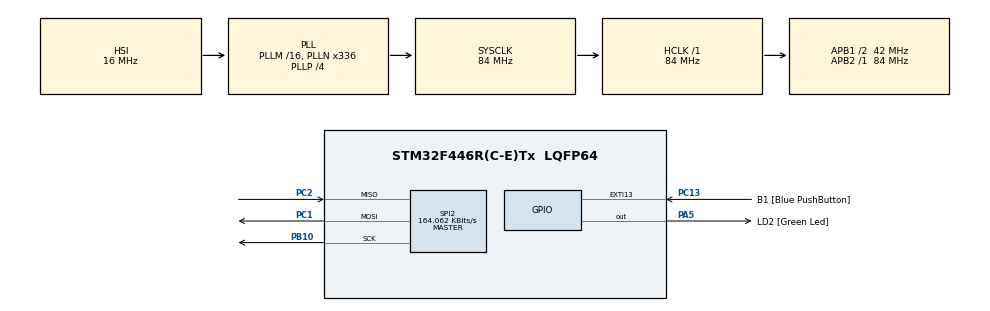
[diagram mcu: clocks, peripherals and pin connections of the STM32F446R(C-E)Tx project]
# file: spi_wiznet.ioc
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Dma.Request0=SPI2_RX
Dma.SPI2_RX.0.Direction=DMA_PERIPH_TO_MEMORY
Dma.SPI2_RX.0.FIFOMode=DMA_FIFOMODE_ENABLE
Dma.SPI2_RX.0.FIFOThreshold=DMA_FIFO_THRESHOLD_FULL
Dma.SPI2_RX.0.Instance=DMA1_Stream3
Dma.SPI2_RX.0.MemBurst=DMA_MBURST_SINGLE
Dma.SPI2_RX.0.MemDataAlignment=DMA_MDATAALIGN_BYTE
Dma.SPI2_RX.0.MemInc=DMA_MINC_ENABLE
Dma.SPI2_RX.0.Mode=DMA_NORMAL
Dma.SPI2_RX.0.PeriphBurst=DMA_PBURST_SINGLE
Dma.SPI2_RX.0.PeriphDataAlignment=DMA_PDATAALIGN_BYTE
Dma.SPI2_RX.0.PeriphInc=DMA_PINC_DISABLE
Dma.SPI2_RX.0.Priority=DMA_PRIORITY_LOW
Mcu.Family=STM32F4
Mcu.Name=STM32F446R(C-E)Tx
Mcu.Package=LQFP64
NVIC.DMA1_Stream3_IRQn=true\:0\:0\:false\:false\:true\:false\:true
NVIC.EXTI15_10_IRQn=true\:0\:0\:false\:false\:true\:true\:true
NVIC.PriorityGroup=NVIC_PRIORITYGROUP_0
NVIC.SPI2_IRQn=true\:0\:0\:false\:false\:true\:true\:true
NVIC.TIM3_IRQn=true\:0\:0\:false\:false\:true\:true\:true
PA13.GPIO_Label=TMS
PA13.Signal=SYS_JTMS-SWDIO
PA14.GPIO_Label=TCK
PA14.Signal=SYS_JTCK-SWCLK
PA2.GPIO_Label=USART_TX
PA2.Signal=USART2_TX
PA3.GPIO_Label=USART_RX
PA3.Signal=USART2_RX
PA5.GPIO_Label=LD2 [Green Led]
PA5.Signal=GPIO_Output
PB10.Mode=Full_Duplex_Master
PB10.Signal=SPI2_SCK
PB3.GPIO_Label=SWO
PB3.Signal=SYS_JTDO-SWO
PC1.Mode=Full_Duplex_Master
PC1.Signal=SPI2_MOSI
PC13.GPIO_Label=B1 [Blue PushButton]
PC13.GPIO_ModeDefaultEXTI=GPIO_MODE_IT_FALLING
PC13.Signal=GPXTI13
PC14-OSC32_IN.Signal=RCC_OSC32_IN
PC15-OSC32_OUT.Signal=RCC_OSC32_OUT
PC2.Mode=Full_Duplex_Master
PC2.Signal=SPI2_MISO
PH0-OSC_IN.Signal=RCC_OSC_IN
PH1-OSC_OUT.Signal=RCC_OSC_OUT
ProjectManager.HeapSize=0x200
ProjectManager.StackSize=0x400
ProjectManager.TargetToolchain=MDK-ARM V5
RCC.AHBFreq_Value=84000000
RCC.APB1CLKDivider=RCC_HCLK_DIV2
RCC.APB1Freq_Value=42000000
RCC.APB1TimFreq_Value=84000000
RCC.APB2Freq_Value=84000000
RCC.APB2TimFreq_Value=84000000
RCC.CortexFreq_Value=84000000
RCC.FLatency-AdvancedSettings=FLASH_LATENCY_2
RCC.HCLKFreq_Value=84000000
RCC.HSE_VALUE=8000000
RCC.HSI_VALUE=16000000
RCC.LSE_VALUE=32768
RCC.PLLN=336
RCC.PLLP=RCC_PLLP_DIV4
RCC.SYSCLKFreq_VALUE=84000000
RCC.SYSCLKSource=RCC_SYSCLKSOURCE_PLLCLK
RCC.USBFreq_Value=168000000
RCC.VCOOutputFreq_Value=336000000
SPI2.BaudRatePrescaler=SPI_BAUDRATEPRESCALER_256
SPI2.CLKPhase=SPI_PHASE_1EDGE
SPI2.CLKPolarity=SPI_POLARITY_LOW
SPI2.CalculateBaudRate=164.062 KBits/s
SPI2.Direction=SPI_DIRECTION_2LINES
SPI2.Mode=SPI_MODE_MASTER
SPI2.VirtualType=VM_MASTER
TIM3.Channel-Output\ Compare1\ No\ Output=TIM_CHANNEL_1
TIM3.Period=1000
TIM3.Prescaler=84
VP_TIM3_VS_OPM.Mode=OPM_bit
VP_TIM3_VS_no_output1.Mode=Output Compare1 No Output
board=NUCLEO-F446RE

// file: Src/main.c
/**
  ******************************************************************************
  * File Name          : main.c
  * Description        : Main program body
  ******************************************************************************
  ** This notice applies to any and all portions of this file
  * that are not between comment pairs USER CODE BEGIN and
  * USER CODE END. Other portions of this file, whether
  * inserted by the user or by software development tools
  * are owned by their respective copyright owners.
  *
  * COPYRIGHT(c) 2020 STMicroelectronics
  *
  * Redistribution and use in source and binary forms, with or without modification,
  * are permitted provided that the following conditions are met:
  *   1. Redistributions of source code must retain the above copyright notice,
  *      this list of conditions and the following disclaimer.
  *   2. Redistributions in binary form must reproduce the above copyright notice,
  *      this list of conditions and the following disclaimer in the documentation
  *      and/or other materials provided with the distribution.
  *   3. Neither the name of STMicroelectronics nor the names of its contributors
  *      may be used to endorse or promote products derived from this software
  *      without specific prior written permission.
  *
  * THIS SOFTWARE IS PROVIDED BY THE COPYRIGHT HOLDERS AND CONTRIBUTORS "AS IS"
  * AND ANY EXPRESS OR IMPLIED WARRANTIES, INCLUDING, BUT NOT LIMITED TO, THE
  * IMPLIED WARRANTIES OF MERCHANTABILITY AND FITNESS FOR A PARTICULAR PURPOSE ARE
  * DISCLAIMED. IN NO EVENT SHALL THE COPYRIGHT HOLDER OR CONTRIBUTORS BE LIABLE
  * FOR ANY DIRECT, INDIRECT, INCIDENTAL, SPECIAL, EXEMPLARY, OR CONSEQUENTIAL
  * DAMAGES (INCLUDING, BUT NOT LIMITED TO, PROCUREMENT OF SUBSTITUTE GOODS OR
  * SERVICES; LOSS OF USE, DATA, OR PROFITS; OR BUSINESS INTERRUPTION) HOWEVER
  * CAUSED AND ON ANY THEORY OF LIABILITY, WHETHER IN CONTRACT, STRICT LIABILITY,
  * OR TORT (INCLUDING NEGLIGENCE OR OTHERWISE) ARISING IN ANY WAY OUT OF THE USE
  * OF THIS SOFTWARE, EVEN IF ADVISED OF THE POSSIBILITY OF SUCH DAMAGE.
  *
  ******************************************************************************
  */

#include "main.h"
#include "stm32f4xx_hal.h"

/* USER CODE BEGIN Includes */
#include "stdbool.h"
#include "w5500.h"
#include "socket.h"
/* USER CODE END Includes */

SPI_HandleTypeDef hspi2;
DMA_HandleTypeDef hdma_spi2_rx;

TIM_HandleTypeDef htim3;

/* USER CODE BEGIN PV */
/* Private variables ---------------------------------------------------------*/
bool send_spi_flag = false;
wiz_NetInfo gWIZNETINFO = {
.mac = {0x00,0x08,0xff,0xad,0x56,0x16},
	.ip = {192,168,0,8},
		.sn = {255,255,255,0},
			.gw = {192,168,0,1},
				.dns = {0,0,0,0},
					.dhcp = NETINFO_STATIC};
/* USER CODE END PV */

void SystemClock_Config(void);
static void MX_GPIO_Init(void);
static void MX_DMA_Init(void);
static void MX_SPI2_Init(void);
static void MX_TIM3_Init(void);

/* USER CODE BEGIN PFP */
/* Private function prototypes -----------------------------------------------*/
void W5500_Select(void);
void W5500_Unselect(void);
void W5500_ReadBuff(uint8_t* buff,uint16_t len);
void W5500_WriteBuff(uint8_t* buff,uint16_t len);
uint8_t W5500_ReadByte(void);
void W5500_WriteByte(uint8_t byte);
/* USER CODE END PFP */

/* USER CODE BEGIN 0 */
//extern HAL_StatusTypeDef InitW5500(InitStructW5500_t Settings);
void InitStructSettings(void);
InitStructW5500_t Settings;
HAL_StatusTypeDef state_send_spi;
uint8_t data_from_spi[4] = {0x00,0x01,0x01,0x00};
uint8_t dest_ip[4] = {192,168,0,1};
uint16_t dest_port = 5777;
uint8_t dest_data[10] = {'1','2','3','4','5','6','7','8','9','0'};
uint8_t https_ok[] =  {"HTTP/1.1 200 OK\r\nContent-Type: text/html\r\nContent-Length:\r\n"};
uint8_t https_data[] = {"<html>\r\n<head>\r\n<meta http-equiv='Content-Type' content='text/html;charset=utf-8'>\r\n<title>МУК на связи)</title>\r\n</head>\r\n<body>\r\n<h1>НИИ Нептун</h1>\r\n<p>Установка сеанса связи удалась</p>\r\n</body>\r\n</html>\r\n\r\n"};//{"<html><head><title>HELLO WORLD!</title></head>"};
uint8_t send_ok[] = {"200 OK"};
uint8_t rx_tx_buffer_size[] = {2,2,2,2,2,2,2,2};
int32_t state_w = 0;
uint32_t leng_data = 0;
uint8_t  addr_gets[4] = {0};
uint16_t port_gets = 0;
uint8_t  data_gets[1024] = {0};
int  len_gets = 0;
/* USER CODE END 0 */

int main(void)
{

  /* MCU Configuration----------------------------------------------------------*/

  /* Reset of all peripherals, Initializes the Flash interface and the Systick. */
  HAL_Init();

  /* Configure the system clock */
  SystemClock_Config();

  /* Initialize all configured peripherals */
  MX_GPIO_Init();
  MX_DMA_Init();
  MX_SPI2_Init();
  MX_TIM3_Init();

  /* USER CODE BEGIN 2 */
	HAL_GPIO_WritePin(W5500_RESET_GPIO_Port,W5500_RESET_Pin,GPIO_PIN_SET);
	//InitStructSettings();
	for(int i = 0; i < 15000;i++)
	{
		__nop();
	}
	//HAL_GPIO_TogglePin(W5500_RESET_GPIO_Port,W5500_RESET_Pin);
	for(uint32_t i = 0; i < 1000000;i++)
	{
		__nop();
	}

	reg_wizchip_cs_cbfunc(W5500_Select,W5500_Unselect);
	reg_wizchip_spi_cbfunc(W5500_ReadByte,W5500_WriteByte);
	reg_wizchip_spiburst_cbfunc(W5500_ReadBuff,W5500_WriteBuff);

	wizchip_init(rx_tx_buffer_size,rx_tx_buffer_size);
	wizchip_setnetinfo(&gWIZNETINFO);
	ctlnetwork(CN_SET_NETINFO,(void*)&gWIZNETINFO);
	/*настроим нулевой сокет как TCP*/
	socket(0,Sn_MR_TCP,80,0);
	/*запустим сервер на нулевом сокете*/
	listen(0);
	/*настроим первый сокет как UDP*/
	socket(1,Sn_MR_UDP,7747,0);

	HAL_TIM_OC_Start_IT(&htim3,TIM_CHANNEL_1);

	/* USER CODE END 2 */

  /* Infinite loop */
  /* USER CODE BEGIN WHILE */
  while (1)
  {
			/*запустим сервер на нулевом сокете*/
//	listen(0);
//		if(send_spi_flag)
//		{
//      //state_w = send(0,dest_data,sizeof(dest_data));
//			state_w = sendto(1,dest_data,sizeof(dest_data),dest_ip,56589);
//			send_spi_flag = false;
//		}
//		len_gets = getSn_RX_RSR(1);
//		if(len_gets != 0)
//		{
//			leng_data =  recvfrom(1,data_gets,len_gets,addr_gets,&port_gets);
//		}
//		len_gets = getSn_RX_RSR(0);
//		if(len_gets != 0)
//		{
//			//leng_data =  recvfrom(0,data_gets,len_gets,addr_gets,&port_gets);
//			getsockopt(0,SO_DESTIP,addr_gets);
//			send(0,https_data,sizeof(https_data));
//			disconnect(0);
//			close(0);
//		}
		socket(0,Sn_MR_TCP,80,0);
		/*запустим сервер на нулевом сокете*/
		listen(0);

		while(getSn_SR(0) == SOCK_LISTEN)
		{
			HAL_Delay(2);
		}

		HAL_Delay(500);

		getsockopt(0,SO_DESTIP,addr_gets);

		len_gets = getSn_RX_RSR(0);

		if(len_gets != 0)
		{
			//leng_data =  recvfrom(0,data_gets,len_gets,addr_gets,&port_gets);

			leng_data =   recv(0, data_gets,len_gets);
	  }
		send(0,https_ok,sizeof(https_ok));
		HAL_Delay(100);
		send(0,https_data,sizeof(https_data));
		HAL_Delay(500);
		disconnect(0);
		HAL_Delay(500);
		close(0);

		HAL_Delay(500);

/* USER CODE END WHILE */

  }

}

/** System Clock Configuration
*/
void SystemClock_Config(void)
{

  RCC_OscInitTypeDef RCC_OscInitStruct;
  RCC_ClkInitTypeDef RCC_ClkInitStruct;

    /**Configure the main internal regulator output voltage
    */
  __HAL_RCC_PWR_CLK_ENABLE();

  __HAL_PWR_VOLTAGESCALING_CONFIG(PWR_REGULATOR_VOLTAGE_SCALE3);

    /**Initializes the CPU, AHB and APB busses clocks
    */
  RCC_OscInitStruct.OscillatorType = RCC_OSCILLATORTYPE_HSI;
  RCC_OscInitStruct.HSIState = RCC_HSI_ON;
  RCC_OscInitStruct.HSICalibrationValue = 16;
  RCC_OscInitStruct.PLL.PLLState = RCC_PLL_ON;
  RCC_OscInitStruct.PLL.PLLSource = RCC_PLLSOURCE_HSI;
  RCC_OscInitStruct.PLL.PLLM = 16;
  RCC_OscInitStruct.PLL.PLLN = 336;
  RCC_OscInitStruct.PLL.PLLP = RCC_PLLP_DIV4;
  RCC_OscInitStruct.PLL.PLLQ = 2;
  RCC_OscInitStruct.PLL.PLLR = 2;
  if (HAL_RCC_OscConfig(&RCC_OscInitStruct) != HAL_OK)
  {
    _Error_Handler(__FILE__, __LINE__);
  }

    /**Initializes the CPU, AHB and APB busses clocks
    */
  RCC_ClkInitStruct.ClockType = RCC_CLOCKTYPE_HCLK|RCC_CLOCKTYPE_SYSCLK
                              |RCC_CLOCKTYPE_PCLK1|RCC_CLOCKTYPE_PCLK2;
  RCC_ClkInitStruct.SYSCLKSource = RCC_SYSCLKSOURCE_PLLCLK;
  RCC_ClkInitStruct.AHBCLKDivider = RCC_SYSCLK_DIV1;
  RCC_ClkInitStruct.APB1CLKDivider = RCC_HCLK_DIV2;
  RCC_ClkInitStruct.APB2CLKDivider = RCC_HCLK_DIV1;

  if (HAL_RCC_ClockConfig(&RCC_ClkInitStruct, FLASH_LATENCY_2) != HAL_OK)
  {
    _Error_Handler(__FILE__, __LINE__);
  }

    /**Configure the Systick interrupt time
    */
  HAL_SYSTICK_Config(HAL_RCC_GetHCLKFreq()/1000);

    /**Configure the Systick
    */
  HAL_SYSTICK_CLKSourceConfig(SYSTICK_CLKSOURCE_HCLK);

  /* SysTick_IRQn interrupt configuration */
  HAL_NVIC_SetPriority(SysTick_IRQn, 0, 0);
}

/* SPI2 init function */
static void MX_SPI2_Init(void)
{

  /* SPI2 parameter configuration*/
  hspi2.Instance = SPI2;
  hspi2.Init.Mode = SPI_MODE_MASTER;
  hspi2.Init.Direction = SPI_DIRECTION_2LINES;
  hspi2.Init.DataSize = SPI_DATASIZE_8BIT;
  hspi2.Init.CLKPolarity = SPI_POLARITY_LOW;
  hspi2.Init.CLKPhase = SPI_PHASE_1EDGE;
  hspi2.Init.NSS = SPI_NSS_SOFT;
  hspi2.Init.BaudRatePrescaler = SPI_BAUDRATEPRESCALER_64;
  hspi2.Init.FirstBit = SPI_FIRSTBIT_MSB;
  hspi2.Init.TIMode = SPI_TIMODE_DISABLE;
  hspi2.Init.CRCCalculation = SPI_CRCCALCULATION_DISABLE;
  hspi2.Init.CRCPolynomial = 10;
  if (HAL_SPI_Init(&hspi2) != HAL_OK)
  {
    _Error_Handler(__FILE__, __LINE__);
  }

}

/* TIM3 init function */
static void MX_TIM3_Init(void)
{

  TIM_MasterConfigTypeDef sMasterConfig;
  TIM_OC_InitTypeDef sConfigOC;

  htim3.Instance = TIM3;
  htim3.Init.Prescaler = 84;
  htim3.Init.CounterMode = TIM_COUNTERMODE_UP;
  htim3.Init.Period = 25000 - 1;
  htim3.Init.ClockDivision = TIM_CLOCKDIVISION_DIV1;
  if (HAL_TIM_OC_Init(&htim3) != HAL_OK)
  {
    _Error_Handler(__FILE__, __LINE__);
  }

  if (HAL_TIM_OnePulse_Init(&htim3, TIM_OPMODE_SINGLE) != HAL_OK)
  {
    _Error_Handler(__FILE__, __LINE__);
  }

  sMasterConfig.MasterOutputTrigger = TIM_TRGO_RESET;
  sMasterConfig.MasterSlaveMode = TIM_MASTERSLAVEMODE_DISABLE;
  if (HAL_TIMEx_MasterConfigSynchronization(&htim3, &sMasterConfig) != HAL_OK)
  {
    _Error_Handler(__FILE__, __LINE__);
  }

  sConfigOC.OCMode = TIM_OCMODE_TIMING;
  sConfigOC.Pulse = 0;
  sConfigOC.OCPolarity = TIM_OCPOLARITY_HIGH;
  sConfigOC.OCFastMode = TIM_OCFAST_DISABLE;
  if (HAL_TIM_OC_ConfigChannel(&htim3, &sConfigOC, TIM_CHANNEL_1) != HAL_OK)
  {
    _Error_Handler(__FILE__, __LINE__);
  }

}

static void MX_DMA_Init(void)
{
  /* DMA controller clock enable */
  __HAL_RCC_DMA1_CLK_ENABLE();

  /* DMA interrupt init */
  /* DMA1_Stream3_IRQn interrupt configuration */
  HAL_NVIC_SetPriority(DMA1_Stream3_IRQn, 0, 0);
  HAL_NVIC_EnableIRQ(DMA1_Stream3_IRQn);

}

/** Configure pins as
        * Analog
        * Input
        * Output
        * EVENT_OUT
        * EXTI
     PA2   ------> USART2_TX
     PA3   ------> USART2_RX
*/
static void MX_GPIO_Init(void)
{

  GPIO_InitTypeDef GPIO_InitStruct;

  /* GPIO Ports Clock Enable */
  __HAL_RCC_GPIOC_CLK_ENABLE();
  __HAL_RCC_GPIOH_CLK_ENABLE();
  __HAL_RCC_GPIOA_CLK_ENABLE();
  __HAL_RCC_GPIOB_CLK_ENABLE();

  /*Configure GPIO pin Output Level */
  HAL_GPIO_WritePin(LD2_GPIO_Port, LD2_Pin, GPIO_PIN_RESET);

  /*Configure GPIO pin : B1_Pin */
  GPIO_InitStruct.Pin = B1_Pin;
  GPIO_InitStruct.Mode = GPIO_MODE_IT_FALLING;
  GPIO_InitStruct.Pull = GPIO_NOPULL;
  HAL_GPIO_Init(B1_GPIO_Port, &GPIO_InitStruct);

  /*Configure GPIO pins : USART_TX_Pin USART_RX_Pin */
  GPIO_InitStruct.Pin = USART_TX_Pin|USART_RX_Pin;
  GPIO_InitStruct.Mode = GPIO_MODE_AF_PP;
  GPIO_InitStruct.Pull = GPIO_NOPULL;
  GPIO_InitStruct.Speed = GPIO_SPEED_FREQ_VERY_HIGH;
  GPIO_InitStruct.Alternate = GPIO_AF7_USART2;
  HAL_GPIO_Init(GPIOA, &GPIO_InitStruct);

  /*Configure GPIO pin : LD2_Pin */
  GPIO_InitStruct.Pin = LD2_Pin;
  GPIO_InitStruct.Mode = GPIO_MODE_OUTPUT_PP;
  GPIO_InitStruct.Pull = GPIO_NOPULL;
  GPIO_InitStruct.Speed = GPIO_SPEED_FREQ_LOW;
  HAL_GPIO_Init(LD2_GPIO_Port, &GPIO_InitStruct);

  GPIO_InitStruct.Pin = GPIO_PIN_8|GPIO_PIN_7;
  GPIO_InitStruct.Mode = GPIO_MODE_OUTPUT_PP;
  GPIO_InitStruct.Pull = GPIO_PULLUP;
  GPIO_InitStruct.Speed = GPIO_SPEED_FREQ_LOW;
  HAL_GPIO_Init(GPIOA, &GPIO_InitStruct);

  /* EXTI interrupt init*/
  HAL_NVIC_SetPriority(EXTI15_10_IRQn, 0, 0);
  HAL_NVIC_EnableIRQ(EXTI15_10_IRQn);

}

/* USER CODE BEGIN 4 */
void W5500_Select(void)
{
	HAL_GPIO_WritePin(W5500_SCS_GPIO_Port,W5500_SCS_Pin,GPIO_PIN_RESET);
}
void W5500_Unselect(void)
{
	HAL_GPIO_WritePin(W5500_SCS_GPIO_Port,W5500_SCS_Pin,GPIO_PIN_SET);
}
void W5500_ReadBuff(uint8_t* buff,uint16_t len)
{
	HAL_SPI_Receive(&hspi2,buff,len,100);
}
void W5500_WriteBuff(uint8_t* buff,uint16_t len)
{
	HAL_SPI_Transmit(&hspi2,buff,len,100);
}
uint8_t W5500_ReadByte(void)
{
	uint8_t byte;
	W5500_ReadBuff(&byte,sizeof(byte));
	return byte;
}
void W5500_WriteByte(uint8_t byte)
{
	W5500_WriteBuff(&byte,sizeof(byte));
}
/* USER CODE END 4 */

void _Error_Handler(char * file, int line)
{
  while(1)
  {
  }
}

/************************ (C) COPYRIGHT STMicroelectronics *****END OF FILE****/
